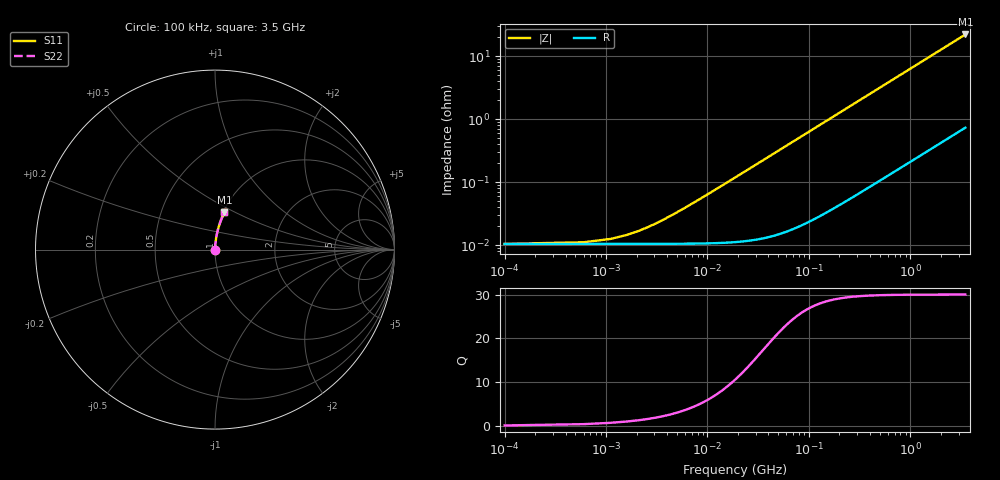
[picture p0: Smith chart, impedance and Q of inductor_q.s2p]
! Created Fri Jul 21 17:20:43 2023
# mhz S ri R 50
! 2 Port Network Data from SP1.SP block
! freq  reS11  imS11  reS21  imS21  reS12  imS12  reS22  imS22
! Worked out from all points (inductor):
!   7001 points, 100 kHz to 3.5 GHz, reference 50 ohm
!   read as one part in series: L = 1 nH near 17.6 MHz
!   highest Q = 30 at 3.499 GHz (marker M1), where L = 1 nH
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0.1  0.000105 6.28e-06  0.9999 -6.28e-06  0.9999 -6.28e-06  0.000105 6.28e-06
8.1  0.000106 0.000509  0.9999 -0.000509  0.9999 -0.000509  0.000106 0.000509
19.1  0.000114 0.0012  0.9999 -0.0012  0.9999 -0.0012  0.000114 0.0012
21.6  0.000116 0.00136  0.9999 -0.00136  0.9999 -0.00136  0.000116 0.00136
27.6  0.000123 0.00173  0.9999 -0.00173  0.9999 -0.00173  0.000123 0.00173
36.1  0.000134 0.00227  0.9999 -0.00227  0.9999 -0.00227  0.000134 0.00227
50.1  0.000158 0.00315  0.9998 -0.00315  0.9998 -0.00315  0.000158 0.00315
67.6  0.000194 0.00425  0.9998 -0.00425  0.9998 -0.00425  0.000194 0.00425
89.6  0.000246 0.00563  0.9998 -0.00563  0.9998 -0.00563  0.000246 0.00563
115.6  0.000316 0.00726  0.9997 -0.00726  0.9997 -0.00726  0.000316 0.00726
149.1  0.000417 0.00936  0.9996 -0.00936  0.9996 -0.00936  0.000417 0.00936
189.1  0.00055 0.0119  0.9995 -0.0119  0.9995 -0.0119  0.00055 0.0119
288.6  0.00094 0.0181  0.9991 -0.0181  0.9991 -0.0181  0.00094 0.0181
419.1  0.00157 0.0263  0.9984 -0.0263  0.9984 -0.0263  0.00157 0.0263
583.6  0.00256 0.0365  0.9974 -0.0365  0.9974 -0.0365  0.00256 0.0365
842.1  0.00454 0.0526  0.9955 -0.0526  0.9955 -0.0526  0.00454 0.0526
1167.1  0.00775 0.0726  0.9923 -0.0726  0.9923 -0.0726  0.00775 0.0726
1750.1  0.0155 0.1079  0.9845 -0.1079  0.9845 -0.1079  0.0155 0.1079
2333.6  0.0256 0.1422  0.9744 -0.1422  0.9744 -0.1422  0.0256 0.1422
2917.1  0.038 0.1753  0.962 -0.1753  0.962 -0.1753  0.038 0.1753
3499.1  0.0524 0.2068  0.9476 -0.2068  0.9476 -0.2068  0.0524 0.2068
3500  0.0524 0.2069  0.9476 -0.2069  0.9476 -0.2069  0.0524 0.2069
